VERSION 5.7 ;
  NOWIREEXTENSIONATPIN ON ;
  DIVIDERCHAR "/" ;
  BUSBITCHARS "[]" ;
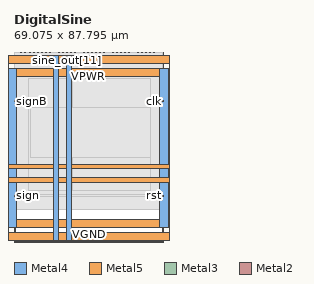
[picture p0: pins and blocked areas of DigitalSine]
MACRO DigitalSine
  CLASS BLOCK ;
  FOREIGN DigitalSine ;
  ORIGIN 0.000 0.000 ;
  SIZE 69.075 BY 87.795 ;
  PIN VGND
    DIRECTION INOUT ;
    USE GROUND ;
    PORT
      LAYER Metal4 ;
        RECT -8.740 0.620 -4.740 86.320 ;
    END
    PORT
      LAYER Metal5 ;
        RECT -8.740 0.620 77.380 4.620 ;
    END
    PORT
      LAYER Metal5 ;
        RECT -8.740 82.320 77.380 86.320 ;
    END
    PORT
      LAYER Metal4 ;
        RECT 73.380 0.620 77.380 86.320 ;
    END
    PORT
      LAYER Metal4 ;
        RECT 24.460 0.620 26.660 86.320 ;
    END
    PORT
      LAYER Metal5 ;
        RECT -8.740 33.820 77.380 36.020 ;
    END
  END VGND
  PIN VPWR
    DIRECTION INOUT ;
    USE POWER ;
    PORT
      LAYER Metal4 ;
        RECT -2.740 6.620 1.260 80.320 ;
    END
    PORT
      LAYER Metal5 ;
        RECT -2.740 6.620 71.380 10.620 ;
    END
    PORT
      LAYER Metal5 ;
        RECT -2.740 76.320 71.380 80.320 ;
    END
    PORT
      LAYER Metal4 ;
        RECT 67.380 6.620 71.380 80.320 ;
    END
    PORT
      LAYER Metal4 ;
        RECT 18.260 0.620 20.460 86.320 ;
    END
    PORT
      LAYER Metal5 ;
        RECT -8.740 27.620 77.380 29.820 ;
    END
  END VPWR
  PIN clk
    DIRECTION INPUT ;
    USE SIGNAL ;
    ANTENNAGATEAREA 0.725400 ;
    PORT
      LAYER Metal3 ;
        RECT 68.675 64.900 69.075 65.300 ;
    END
  END clk
  PIN rst
    DIRECTION INPUT ;
    USE SIGNAL ;
    ANTENNAGATEAREA 0.180700 ;
    PORT
      LAYER Metal3 ;
        RECT 68.675 21.220 69.075 21.620 ;
    END
  END rst
  PIN sign
    DIRECTION OUTPUT ;
    USE SIGNAL ;
    ANTENNADIFFAREA 0.706800 ;
    PORT
      LAYER Metal3 ;
        RECT 0.000 21.220 0.400 21.620 ;
    END
  END sign
  PIN signB
    DIRECTION OUTPUT ;
    USE SIGNAL ;
    ANTENNADIFFAREA 0.706800 ;
    PORT
      LAYER Metal3 ;
        RECT 0.000 64.900 0.400 65.300 ;
    END
  END signB
  PIN sine_out[0]
    DIRECTION OUTPUT ;
    USE SIGNAL ;
    ANTENNADIFFAREA 0.706800 ;
    PORT
      LAYER Metal2 ;
        RECT 3.160 87.395 3.560 87.795 ;
    END
  END sine_out[0]
  PIN sine_out[10]
    DIRECTION OUTPUT ;
    USE SIGNAL ;
    ANTENNADIFFAREA 0.706800 ;
    PORT
      LAYER Metal2 ;
        RECT 22.360 87.395 22.760 87.795 ;
    END
  END sine_out[10]
  PIN sine_out[11]
    DIRECTION OUTPUT ;
    USE SIGNAL ;
    ANTENNADIFFAREA 0.706800 ;
    PORT
      LAYER Metal2 ;
        RECT 24.280 87.395 24.680 87.795 ;
    END
  END sine_out[11]
  PIN sine_out[12]
    DIRECTION OUTPUT ;
    USE SIGNAL ;
    ANTENNADIFFAREA 0.706800 ;
    PORT
      LAYER Metal2 ;
        RECT 26.200 87.395 26.600 87.795 ;
    END
  END sine_out[12]
  PIN sine_out[13]
    DIRECTION OUTPUT ;
    USE SIGNAL ;
    ANTENNADIFFAREA 0.706800 ;
    PORT
      LAYER Metal2 ;
        RECT 28.120 87.395 28.520 87.795 ;
    END
  END sine_out[13]
  PIN sine_out[14]
    DIRECTION OUTPUT ;
    USE SIGNAL ;
    ANTENNADIFFAREA 0.706800 ;
    PORT
      LAYER Metal2 ;
        RECT 30.040 87.395 30.440 87.795 ;
    END
  END sine_out[14]
  PIN sine_out[15]
    DIRECTION OUTPUT ;
    USE SIGNAL ;
    ANTENNADIFFAREA 0.706800 ;
    PORT
      LAYER Metal2 ;
        RECT 31.960 87.395 32.360 87.795 ;
    END
  END sine_out[15]
  PIN sine_out[16]
    DIRECTION OUTPUT ;
    USE SIGNAL ;
    ANTENNADIFFAREA 0.706800 ;
    PORT
      LAYER Metal2 ;
        RECT 33.880 87.395 34.280 87.795 ;
    END
  END sine_out[16]
  PIN sine_out[17]
    DIRECTION OUTPUT ;
    USE SIGNAL ;
    ANTENNADIFFAREA 0.706800 ;
    PORT
      LAYER Metal2 ;
        RECT 35.800 87.395 36.200 87.795 ;
    END
  END sine_out[17]
  PIN sine_out[18]
    DIRECTION OUTPUT ;
    USE SIGNAL ;
    ANTENNADIFFAREA 0.706800 ;
    PORT
      LAYER Metal2 ;
        RECT 37.720 87.395 38.120 87.795 ;
    END
  END sine_out[18]
  PIN sine_out[19]
    DIRECTION OUTPUT ;
    USE SIGNAL ;
    ANTENNADIFFAREA 0.706800 ;
    PORT
      LAYER Metal2 ;
        RECT 39.640 87.395 40.040 87.795 ;
    END
  END sine_out[19]
  PIN sine_out[1]
    DIRECTION OUTPUT ;
    USE SIGNAL ;
    ANTENNADIFFAREA 0.706800 ;
    PORT
      LAYER Metal2 ;
        RECT 5.080 87.395 5.480 87.795 ;
    END
  END sine_out[1]
  PIN sine_out[20]
    DIRECTION OUTPUT ;
    USE SIGNAL ;
    ANTENNADIFFAREA 0.706800 ;
    PORT
      LAYER Metal2 ;
        RECT 41.560 87.395 41.960 87.795 ;
    END
  END sine_out[20]
  PIN sine_out[21]
    DIRECTION OUTPUT ;
    USE SIGNAL ;
    ANTENNADIFFAREA 0.706800 ;
    PORT
      LAYER Metal2 ;
        RECT 43.480 87.395 43.880 87.795 ;
    END
  END sine_out[21]
  PIN sine_out[22]
    DIRECTION OUTPUT ;
    USE SIGNAL ;
    ANTENNADIFFAREA 0.706800 ;
    PORT
      LAYER Metal2 ;
        RECT 45.400 87.395 45.800 87.795 ;
    END
  END sine_out[22]
  PIN sine_out[23]
    DIRECTION OUTPUT ;
    USE SIGNAL ;
    ANTENNADIFFAREA 0.706800 ;
    PORT
      LAYER Metal2 ;
        RECT 47.320 87.395 47.720 87.795 ;
    END
  END sine_out[23]
  PIN sine_out[24]
    DIRECTION OUTPUT ;
    USE SIGNAL ;
    ANTENNADIFFAREA 0.706800 ;
    PORT
      LAYER Metal2 ;
        RECT 49.240 87.395 49.640 87.795 ;
    END
  END sine_out[24]
  PIN sine_out[25]
    DIRECTION OUTPUT ;
    USE SIGNAL ;
    ANTENNADIFFAREA 0.706800 ;
    PORT
      LAYER Metal2 ;
        RECT 51.160 87.395 51.560 87.795 ;
    END
  END sine_out[25]
  PIN sine_out[26]
    DIRECTION OUTPUT ;
    USE SIGNAL ;
    ANTENNADIFFAREA 0.706800 ;
    PORT
      LAYER Metal2 ;
        RECT 53.080 87.395 53.480 87.795 ;
    END
  END sine_out[26]
  PIN sine_out[27]
    DIRECTION OUTPUT ;
    USE SIGNAL ;
    ANTENNADIFFAREA 0.706800 ;
    PORT
      LAYER Metal2 ;
        RECT 55.000 87.395 55.400 87.795 ;
    END
  END sine_out[27]
  PIN sine_out[28]
    DIRECTION OUTPUT ;
    USE SIGNAL ;
    ANTENNADIFFAREA 0.706800 ;
    PORT
      LAYER Metal2 ;
        RECT 56.920 87.395 57.320 87.795 ;
    END
  END sine_out[28]
  PIN sine_out[29]
    DIRECTION OUTPUT ;
    USE SIGNAL ;
    ANTENNADIFFAREA 0.706800 ;
    PORT
      LAYER Metal2 ;
        RECT 58.840 87.395 59.240 87.795 ;
    END
  END sine_out[29]
  PIN sine_out[2]
    DIRECTION OUTPUT ;
    USE SIGNAL ;
    ANTENNADIFFAREA 0.706800 ;
    PORT
      LAYER Metal2 ;
        RECT 7.000 87.395 7.400 87.795 ;
    END
  END sine_out[2]
  PIN sine_out[30]
    DIRECTION OUTPUT ;
    USE SIGNAL ;
    ANTENNADIFFAREA 0.706800 ;
    PORT
      LAYER Metal2 ;
        RECT 60.760 87.395 61.160 87.795 ;
    END
  END sine_out[30]
  PIN sine_out[31]
    DIRECTION OUTPUT ;
    USE SIGNAL ;
    ANTENNADIFFAREA 0.706800 ;
    PORT
      LAYER Metal2 ;
        RECT 62.680 87.395 63.080 87.795 ;
    END
  END sine_out[31]
  PIN sine_out[32]
    DIRECTION OUTPUT ;
    USE SIGNAL ;
    ANTENNADIFFAREA 0.706800 ;
    PORT
      LAYER Metal2 ;
        RECT 64.600 87.395 65.000 87.795 ;
    END
  END sine_out[32]
  PIN sine_out[3]
    DIRECTION OUTPUT ;
    USE SIGNAL ;
    ANTENNADIFFAREA 0.706800 ;
    PORT
      LAYER Metal2 ;
        RECT 8.920 87.395 9.320 87.795 ;
    END
  END sine_out[3]
  PIN sine_out[4]
    DIRECTION OUTPUT ;
    USE SIGNAL ;
    ANTENNADIFFAREA 0.706800 ;
    PORT
      LAYER Metal2 ;
        RECT 10.840 87.395 11.240 87.795 ;
    END
  END sine_out[4]
  PIN sine_out[5]
    DIRECTION OUTPUT ;
    USE SIGNAL ;
    ANTENNADIFFAREA 0.706800 ;
    PORT
      LAYER Metal2 ;
        RECT 12.760 87.395 13.160 87.795 ;
    END
  END sine_out[5]
  PIN sine_out[6]
    DIRECTION OUTPUT ;
    USE SIGNAL ;
    ANTENNADIFFAREA 0.706800 ;
    PORT
      LAYER Metal2 ;
        RECT 14.680 87.395 15.080 87.795 ;
    END
  END sine_out[6]
  PIN sine_out[7]
    DIRECTION OUTPUT ;
    USE SIGNAL ;
    ANTENNADIFFAREA 0.706800 ;
    PORT
      LAYER Metal2 ;
        RECT 16.600 87.395 17.000 87.795 ;
    END
  END sine_out[7]
  PIN sine_out[8]
    DIRECTION OUTPUT ;
    USE SIGNAL ;
    ANTENNADIFFAREA 0.706800 ;
    PORT
      LAYER Metal2 ;
        RECT 18.520 87.395 18.920 87.795 ;
    END
  END sine_out[8]
  PIN sine_out[9]
    DIRECTION OUTPUT ;
    USE SIGNAL ;
    ANTENNADIFFAREA 0.706800 ;
    PORT
      LAYER Metal2 ;
        RECT 20.440 87.395 20.840 87.795 ;
    END
  END sine_out[9]
  OBS
      LAYER GatPoly ;
        RECT 5.760 14.970 62.880 71.970 ;
      LAYER Metal1 ;
        RECT 5.760 14.900 62.880 72.040 ;
      LAYER Metal2 ;
        RECT 3.770 87.185 4.870 87.695 ;
        RECT 5.690 87.185 6.790 87.695 ;
        RECT 7.610 87.185 8.710 87.695 ;
        RECT 9.530 87.185 10.630 87.695 ;
        RECT 11.450 87.185 12.550 87.695 ;
        RECT 13.370 87.185 14.470 87.695 ;
        RECT 15.290 87.185 16.390 87.695 ;
        RECT 17.210 87.185 18.310 87.695 ;
        RECT 19.130 87.185 20.230 87.695 ;
        RECT 21.050 87.185 22.150 87.695 ;
        RECT 22.970 87.185 24.070 87.695 ;
        RECT 24.890 87.185 25.990 87.695 ;
        RECT 26.810 87.185 27.910 87.695 ;
        RECT 28.730 87.185 29.830 87.695 ;
        RECT 30.650 87.185 31.750 87.695 ;
        RECT 32.570 87.185 33.670 87.695 ;
        RECT 34.490 87.185 35.590 87.695 ;
        RECT 36.410 87.185 37.510 87.695 ;
        RECT 38.330 87.185 39.430 87.695 ;
        RECT 40.250 87.185 41.350 87.695 ;
        RECT 42.170 87.185 43.270 87.695 ;
        RECT 44.090 87.185 45.190 87.695 ;
        RECT 46.010 87.185 47.110 87.695 ;
        RECT 47.930 87.185 49.030 87.695 ;
        RECT 49.850 87.185 50.950 87.695 ;
        RECT 51.770 87.185 52.870 87.695 ;
        RECT 53.690 87.185 54.790 87.695 ;
        RECT 55.610 87.185 56.710 87.695 ;
        RECT 57.530 87.185 58.630 87.695 ;
        RECT 59.450 87.185 60.550 87.695 ;
        RECT 61.370 87.185 62.470 87.695 ;
        RECT 63.290 87.185 64.390 87.695 ;
        RECT 3.255 14.975 64.905 87.185 ;
      LAYER Metal3 ;
        RECT 0.400 65.510 68.675 87.460 ;
        RECT 0.610 64.690 68.465 65.510 ;
        RECT 0.400 21.830 68.675 64.690 ;
        RECT 0.610 21.010 68.465 21.830 ;
        RECT 0.400 15.020 68.675 21.010 ;
      LAYER Metal4 ;
        RECT 6.620 23.795 18.050 75.745 ;
        RECT 20.670 23.795 24.250 75.745 ;
        RECT 26.870 23.795 62.985 75.745 ;
      LAYER Metal5 ;
        RECT 7.535 38.960 63.025 62.260 ;
  END
END DigitalSine
END LIBRARY

